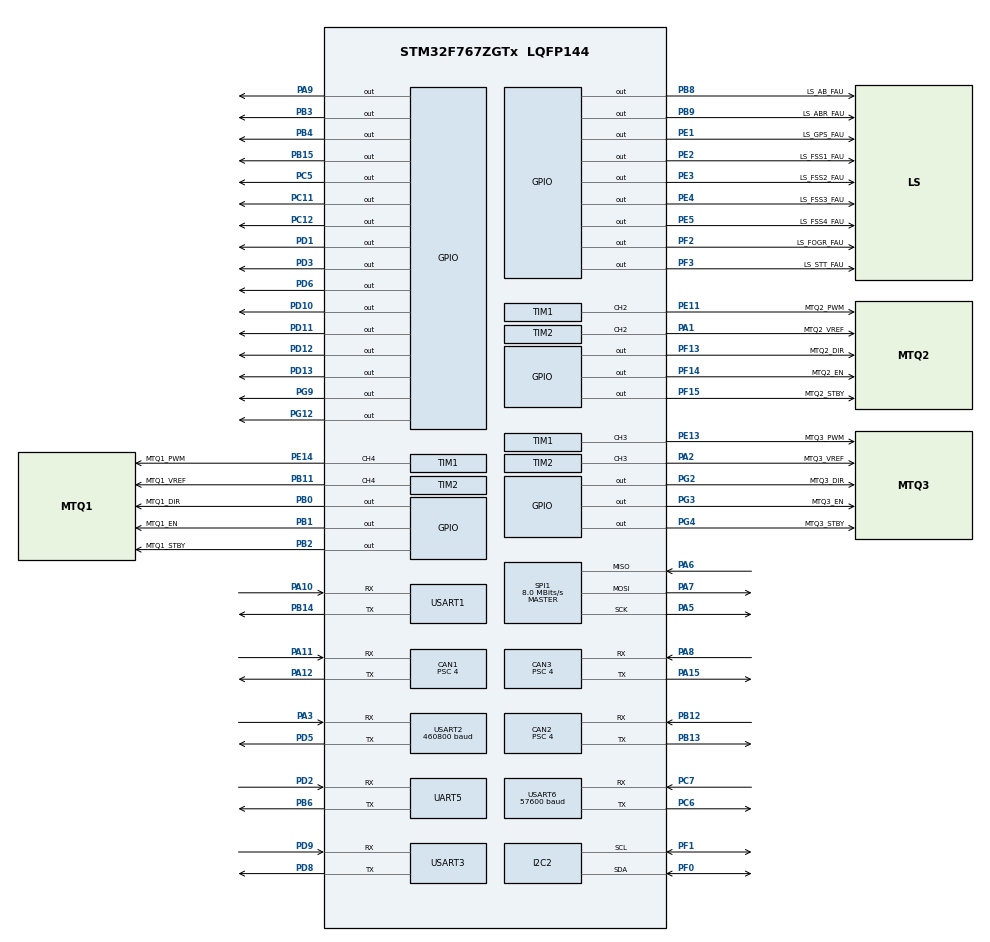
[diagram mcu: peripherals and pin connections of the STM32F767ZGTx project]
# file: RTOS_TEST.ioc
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CAN1.BS1=CAN_BS1_6TQ
CAN1.CalculateBaudRate=1000000
CAN1.CalculateTimeBit=1000
CAN1.CalculateTimeQuantum=125.0
CAN1.Prescaler=4
CAN1.RFLM=DISABLE
CAN1.TXFP=DISABLE
CAN2.BS1=CAN_BS1_6TQ
CAN2.CalculateBaudRate=1000000
CAN2.CalculateTimeBit=1000
CAN2.CalculateTimeQuantum=125.0
CAN2.Prescaler=4
CAN3.BS1=CAN_BS1_6TQ
CAN3.CalculateBaudRate=1000000
CAN3.CalculateTimeBit=1000
CAN3.CalculateTimeQuantum=125.0
CAN3.Prescaler=4
Dma.Request0=USART2_RX
Dma.Request1=USART6_RX
Dma.USART2_RX.0.Direction=DMA_PERIPH_TO_MEMORY
Dma.USART2_RX.0.FIFOMode=DMA_FIFOMODE_DISABLE
Dma.USART2_RX.0.Instance=DMA1_Stream5
Dma.USART2_RX.0.MemDataAlignment=DMA_MDATAALIGN_BYTE
Dma.USART2_RX.0.MemInc=DMA_MINC_ENABLE
Dma.USART2_RX.0.Mode=DMA_NORMAL
Dma.USART2_RX.0.PeriphDataAlignment=DMA_PDATAALIGN_BYTE
Dma.USART2_RX.0.PeriphInc=DMA_PINC_DISABLE
Dma.USART2_RX.0.Priority=DMA_PRIORITY_VERY_HIGH
Dma.USART6_RX.1.Direction=DMA_PERIPH_TO_MEMORY
Dma.USART6_RX.1.FIFOMode=DMA_FIFOMODE_DISABLE
Dma.USART6_RX.1.Instance=DMA2_Stream1
Dma.USART6_RX.1.MemDataAlignment=DMA_MDATAALIGN_BYTE
Dma.USART6_RX.1.MemInc=DMA_MINC_ENABLE
Dma.USART6_RX.1.Mode=DMA_NORMAL
Dma.USART6_RX.1.PeriphDataAlignment=DMA_PDATAALIGN_BYTE
Dma.USART6_RX.1.PeriphInc=DMA_PINC_DISABLE
Dma.USART6_RX.1.Priority=DMA_PRIORITY_MEDIUM
FATFS._MAX_SS=4096
FATFS._USE_LFN=2
FREERTOS.CMSIS_version-CMSIS_V2=undefined
FREERTOS.Tasks01=defaultTask,24,128,StartDefaultTask,Default,NULL,Dynamic,NULL,NULL
FREERTOS.configTOTAL_HEAP_SIZE=125000
FREERTOS.configUSE_NEWLIB_REENTRANT=1
FREERTOS.configUSE_STATS_FORMATTING_FUNCTIONS=1
I2C2.Timing=0x00707CBB
Mcu.Family=STM32F7
Mcu.Name=STM32F767ZGTx
Mcu.Package=LQFP144
NVIC.CAN1_RX0_IRQn=true\:5\:0\:true\:false\:true\:true\:true\:true\:true
NVIC.CAN1_RX1_IRQn=true\:5\:0\:true\:false\:true\:true\:true\:true\:true
NVIC.CAN1_SCE_IRQn=true\:5\:0\:false\:false\:true\:true\:true\:true\:true
NVIC.CAN1_TX_IRQn=true\:5\:0\:false\:false\:true\:true\:true\:true\:true
NVIC.CAN2_RX0_IRQn=true\:5\:0\:false\:false\:true\:true\:true\:true\:true
NVIC.CAN2_RX1_IRQn=true\:5\:0\:false\:false\:true\:true\:true\:true\:true
NVIC.CAN3_RX0_IRQn=true\:5\:0\:false\:false\:true\:true\:true\:true\:true
NVIC.DMA1_Stream5_IRQn=true\:6\:0\:true\:false\:true\:true\:false\:true\:true
NVIC.DMA2_Stream1_IRQn=true\:5\:0\:false\:false\:true\:true\:false\:true\:true
NVIC.PriorityGroup=NVIC_PRIORITYGROUP_4
NVIC.TIM6_DAC_IRQn=true\:15\:0\:false\:false\:true\:false\:false\:true\:true
NVIC.TimeBase=TIM6_DAC_IRQn
NVIC.TimeBaseIP=TIM6
NVIC.UART5_IRQn=true\:5\:0\:false\:false\:true\:true\:true\:true\:true
NVIC.USART2_IRQn=true\:6\:0\:true\:false\:true\:true\:true\:true\:true
NVIC.USART6_IRQn=true\:5\:0\:false\:false\:true\:true\:true\:true\:true
PA1.GPIO_Label=MTQ2_VREF
PA1.Signal=S_TIM2_CH2
PA10.Mode=Asynchronous
PA10.Signal=USART1_RX
PA11.Mode=CAN_Activate
PA11.Signal=CAN1_RX
PA12.Mode=CAN_Activate
PA12.Signal=CAN1_TX
PA13.Mode=Serial_Wire
PA13.Signal=SYS_JTMS-SWDIO
PA14.Mode=Serial_Wire
PA14.Signal=SYS_JTCK-SWCLK
PA15.Mode=CAN_Activate
PA15.Signal=CAN3_TX
PA2.GPIO_Label=MTQ3_VREF
PA2.Signal=S_TIM2_CH3
PA3.Mode=Asynchronous
PA3.Signal=USART2_RX
PA5.Mode=Full_Duplex_Master
PA5.Signal=SPI1_SCK
PA6.Mode=Full_Duplex_Master
PA6.Signal=SPI1_MISO
PA7.Mode=Full_Duplex_Master
PA7.Signal=SPI1_MOSI
PA8.Mode=CAN_Activate
PA8.Signal=CAN3_RX
PA9.Signal=GPIO_Output
PB0.GPIO_Label=MTQ1_DIR
PB0.Signal=GPIO_Output
PB1.GPIO_Label=MTQ1_EN
PB1.Signal=GPIO_Output
PB11.GPIO_Label=MTQ1_VREF
PB11.Signal=S_TIM2_CH4
PB12.Mode=CAN_Activate
PB12.Signal=CAN2_RX
PB13.Mode=CAN_Activate
PB13.Signal=CAN2_TX
PB14.Mode=Asynchronous
PB14.Signal=USART1_TX
PB15.Signal=GPIO_Output
PB2.GPIO_Label=MTQ1_STBY
PB2.Signal=GPIO_Output
PB3.Signal=GPIO_Output
PB4.Signal=GPIO_Output
PB6.Mode=Asynchronous
PB6.Signal=UART5_TX
PB8.GPIO_Label=LS_AB_FAU
PB8.PinState=GPIO_PIN_SET
PB8.Signal=GPIO_Output
PB9.GPIO_Label=LS_ABR_FAU
PB9.PinState=GPIO_PIN_SET
PB9.Signal=GPIO_Output
PC11.Signal=GPIO_Output
PC12.Signal=GPIO_Output
PC5.Signal=GPIO_Output
PC6.Mode=Asynchronous
PC6.Signal=USART6_TX
PC7.Mode=Asynchronous
PC7.Signal=USART6_RX
PD1.Signal=GPIO_Output
PD10.Signal=GPIO_Output
PD11.Signal=GPIO_Output
PD12.Signal=GPIO_Output
PD13.Signal=GPIO_Output
PD2.Mode=Asynchronous
PD2.Signal=UART5_RX
PD3.Signal=GPIO_Output
PD5.Mode=Asynchronous
PD5.Signal=USART2_TX
PD6.Signal=GPIO_Output
PD8.Mode=Asynchronous
PD8.Signal=USART3_TX
PD9.Mode=Asynchronous
PD9.Signal=USART3_RX
PE1.GPIO_Label=LS_GPS_FAU
PE1.PinState=GPIO_PIN_SET
PE1.Signal=GPIO_Output
PE11.GPIO_Label=MTQ2_PWM
PE11.Signal=S_TIM1_CH2
PE13.GPIO_Label=MTQ3_PWM
PE13.Signal=S_TIM1_CH3
PE14.GPIO_Label=MTQ1_PWM
PE14.Signal=S_TIM1_CH4
PE2.GPIO_Label=LS_FSS1_FAU
PE2.PinState=GPIO_PIN_SET
PE2.Signal=GPIO_Output
PE3.GPIO_Label=LS_FSS2_FAU
PE3.PinState=GPIO_PIN_SET
PE3.Signal=GPIO_Output
PE4.GPIO_Label=LS_FSS3_FAU
PE4.PinState=GPIO_PIN_SET
PE4.Signal=GPIO_Output
PE5.GPIO_Label=LS_FSS4_FAU
PE5.PinState=GPIO_PIN_SET
PE5.Signal=GPIO_Output
PF0.Mode=I2C
PF0.Signal=I2C2_SDA
PF1.Mode=I2C
PF1.Signal=I2C2_SCL
PF13.GPIO_Label=MTQ2_DIR
PF13.Signal=GPIO_Output
PF14.GPIO_Label=MTQ2_EN
PF14.Signal=GPIO_Output
PF15.GPIO_Label=MTQ2_STBY
PF15.Signal=GPIO_Output
PF2.GPIO_Label=LS_FOGR_FAU
PF2.PinState=GPIO_PIN_SET
PF2.Signal=GPIO_Output
PF3.GPIO_Label=LS_STT_FAU
PF3.PinState=GPIO_PIN_SET
PF3.Signal=GPIO_Output
PG0.Signal=EVENTOUT
PG12.PinState=GPIO_PIN_SET
PG12.Signal=GPIO_Output
PG2.GPIO_Label=MTQ3_DIR
PG2.Signal=GPIO_Output
PG3.GPIO_Label=MTQ3_EN
PG3.Signal=GPIO_Output
PG4.GPIO_Label=MTQ3_STBY
PG4.Signal=GPIO_Output
PG9.PinState=GPIO_PIN_SET
PG9.Signal=GPIO_Output
PH0/OSC_IN.Mode=HSE-External-Oscillator
PH0/OSC_IN.Signal=RCC_OSC_IN
PH1/OSC_OUT.Mode=HSE-External-Oscillator
PH1/OSC_OUT.Signal=RCC_OSC_OUT
ProjectManager.HeapSize=0x200
ProjectManager.StackSize=0x400
ProjectManager.TargetToolchain=STM32CubeIDE
RCC.AHBFreq_Value=128000000
RCC.APB1CLKDivider=RCC_HCLK_DIV4
RCC.APB1Freq_Value=32000000
RCC.APB1TimFreq_Value=64000000
RCC.APB2CLKDivider=RCC_HCLK_DIV2
RCC.APB2Freq_Value=64000000
RCC.APB2TimFreq_Value=128000000
RCC.CortexFreq_Value=128000000
RCC.HCLKFreq_Value=128000000
RCC.HSE_VALUE=25000000
RCC.HSI_VALUE=16000000
RCC.LSE_VALUE=32768
RCC.PLLM=25
RCC.PLLN=256
RCC.PLLSourceVirtual=RCC_PLLSOURCE_HSE
RCC.SYSCLKFreq_VALUE=128000000
RCC.SYSCLKSource=RCC_SYSCLKSOURCE_PLLCLK
RCC.USBFreq_Value=128000000
RCC.VCOOutputFreq_Value=256000000
SH.S_TIM1_CH2.0=TIM1_CH2,PWM Generation2 CH2
SH.S_TIM1_CH3.0=TIM1_CH3,PWM Generation3 CH3
SH.S_TIM1_CH4.0=TIM1_CH4,PWM Generation4 CH4
SH.S_TIM2_CH2.0=TIM2_CH2,PWM Generation2 CH2
SH.S_TIM2_CH3.0=TIM2_CH3,PWM Generation3 CH3
SH.S_TIM2_CH4.0=TIM2_CH4,PWM Generation4 CH4
SPI1.BaudRatePrescaler=SPI_BAUDRATEPRESCALER_8
SPI1.CRCCalculation=SPI_CRCCALCULATION_DISABLE
SPI1.CalculateBaudRate=8.0 MBits/s
SPI1.DataSize=SPI_DATASIZE_8BIT
SPI1.Direction=SPI_DIRECTION_2LINES
SPI1.Mode=SPI_MODE_MASTER
SPI1.VirtualType=VM_MASTER
TIM1.Channel-PWM\ Generation2\ CH2=TIM_CHANNEL_2
TIM1.Channel-PWM\ Generation3\ CH3=TIM_CHANNEL_3
TIM1.Channel-PWM\ Generation4\ CH4=TIM_CHANNEL_4
TIM1.Period=99
TIM1.Prescaler=31
TIM2.Channel-PWM\ Generation2\ CH2=TIM_CHANNEL_2
TIM2.Channel-PWM\ Generation3\ CH3=TIM_CHANNEL_3
TIM2.Channel-PWM\ Generation4\ CH4=TIM_CHANNEL_4
TIM2.Period=99
TIM2.Prescaler=31
USART1.VirtualMode-Asynchronous=VM_ASYNC
USART2.BaudRate=460800
USART2.VirtualMode-Asynchronous=VM_ASYNC
USART3.VirtualMode-Asynchronous=VM_ASYNC
USART6.BaudRate=57600
USART6.VirtualMode-Asynchronous=VM_ASYNC
VP_FATFS_VS_Generic.Mode=User_defined
VP_FREERTOS_VS_CMSIS_V2.Mode=CMSIS_V2
VP_SYS_VS_tim6.Mode=TIM6
board=custom

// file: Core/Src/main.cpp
/* USER CODE BEGIN Header */
/**
  ******************************************************************************
  * @file           : main.c
  * @brief          : Main program body
  ******************************************************************************
  * @attention
  *
  * Copyright (c) 2024 STMicroelectronics.
  * All rights reserved.
  *
  * This software is licensed under terms that can be found in the LICENSE file
  * in the root directory of this software component.
  * If no LICENSE file comes with this software, it is provided AS-IS.
  *
  ******************************************************************************
  */
/* USER CODE END Header */
#include <stdio.h>
#include <string.h>
#include <unistd.h>
#include <stdlib.h>
#include "main.h"
#include "cmsis_os.h"
#include "can.h"
#include "fatfs.h"
#include "spi.h"
#include "tim.h"
#include "i2c.h"
#include "usart.h"
#include "gpio.h"
#include "dma.h"

#include <include/csp/csp.h>
#include <include/csp/arch/csp_thread.h>
#include "src/drivers/can_stm/f767zgtx_can.h"

/* USER CODE BEGIN PD */
#define MY_SERVER_PORT		10
#define PORT_REGISTER		20
/* USER CODE END PD */

/* USER CODE BEGIN PV */
const char *rtable = NULL;

/* USER CODE END PV */

void SystemClock_Config(void);
void MX_FREERTOS_Init(void);
/* USER CODE BEGIN PFP */

extern void service_adcs_register(csp_conn_t *conn, csp_packet_t *packet);
static CSP_DEFINE_TASK(task_server);
static CSP_DEFINE_TASK(task_client);
int test_csp_server_task(unsigned int task_stack_size,unsigned int task_priority);
int test_csp_client_task(unsigned int task_stack_size,unsigned int task_priority);
int test_csp_server_client_task(unsigned int task_stack_size,unsigned int task_priority);

/* USER CODE END PFP */

/* USER CODE BEGIN 0 */
CSP_DEFINE_TASK(task_server) {

	csp_log_info("Server task started");

	/* Create socket with no specific socket options, e.g. accepts CRC32, HMAC, XTEA, etc. if enabled during compilation */
	csp_socket_t *sock = csp_socket(CSP_SO_NONE);

	/* Bind socket to all ports, e.g. all incoming connections will be handled here */
	csp_bind(sock, CSP_ANY);

	/* Create a backlog of 10 connections, i.e. up to 10 new connections can be queued */
	csp_listen(sock, 10);

	/* Wait for connections and then process packets on the connection */
	while (1) {

		/* Wait for a new connection, 10000 mS timeout */
		csp_conn_t *conn;
		if ((conn = csp_accept(sock, 10000)) == NULL) {
			/* timeout */
			continue;
		}

		/* Read packets on connection, timout is 100 mS */
		csp_packet_t *packet;
		while ((packet = csp_read(conn, 50)) != NULL) {
			switch (csp_conn_dport(conn)) {
			case MY_SERVER_PORT:
				/* Process packet here */
				csp_log_info("Packet received on MY_SERVER_PORT: %s", (char *) packet->data);
				csp_buffer_free(packet);

	//			service_react_v(conn, packet);
				break;

			case PORT_REGISTER:
				service_adcs_register(conn, packet);
				break;

			default:
				/* Call the default CSP service handler, handle pings, buffer use, etc. */
				csp_service_handler(conn, packet);
				break;
			}
		}

		/* Close current connection */
		csp_close(conn);

	}

	return CSP_TASK_RETURN;

}
/* End of server task */

/* Client task sending requests to server task */
CSP_DEFINE_TASK(task_client) {

	csp_log_info("Client task started");

	unsigned int count = 0;

	while (1) {
//csp_ps(12, 1000);csp_ps(16, 1000);csp_ps(21, 1000);
		csp_sleep_ms(1000);

	}

	return CSP_TASK_RETURN;
}
/* End of client task */

int test_csp_server_task(unsigned int task_stack_size,
		unsigned int task_priority) {
	int ret = csp_thread_create(task_server, "SERVER", task_stack_size, NULL,
			task_priority, NULL);
	if (ret != 0) {
		csp_log_error("Failed to start server task, error: %d", ret);
		return ret;
	}
	return CSP_ERR_NONE;
}

int test_csp_client_task(unsigned int task_stack_size,
		unsigned int task_priority) {
	int ret = csp_thread_create(task_client, "CLIENT", task_stack_size, NULL,
			task_priority, NULL);
	if (ret != 0) {
		csp_log_error("Failed to start client task, error: %d", ret);
		return ret;
	}
	return CSP_ERR_NONE;
}

int test_csp_server_client_task(unsigned int task_stack_size,
		unsigned int task_priority) {
	int ret1 = csp_thread_create(task_server, "SERVER", task_stack_size, NULL,
			task_priority, NULL);
	if (ret1 != 0) {
		csp_log_error("Failed to start server task, error: %d", ret1);
		return ret1;
	}
	int ret2 = csp_thread_create(task_client, "CLIENT", task_stack_size, NULL,
			task_priority, NULL);
	if (ret2 != 0) {
		csp_log_error("Failed to start client task, error: %d", ret2);
		return ret2;
	}
	return CSP_ERR_NONE;
}

/* USER CODE END 0 */

int main(void)
{

  /* MCU Configuration--------------------------------------------------------*/

  /* Reset of all peripherals, Initializes the Flash interface and the Systick. */
  HAL_Init();

  /* Configure the system clock */
  SystemClock_Config();

  /* Initialize all configured peripherals */
  MX_DMA_Init();
  MX_GPIO_Init();
  MX_UART5_Init();
  MX_CAN1_Init();
  MX_CAN2_Init();
  MX_CAN3_Init();
  MX_USART3_UART_Init();
  MX_USART6_UART_Init();
  MX_TIM1_Init();
  MX_TIM2_Init();
  MX_SPI1_Init();
  MX_I2C2_Init();
//  MX_FATFS_Init();
  MX_USART2_UART_Init();
  MX_USART1_UART_Init();
  CAN_FilterConfig();
  HAL_CAN_ActivateNotification(&hcan2, CAN_IT_RX_FIFO0_MSG_PENDING);
  HAL_CAN_ActivateNotification(&hcan3, CAN_IT_RX_FIFO0_MSG_PENDING);

//	HAL_CAN_ActivateNotification(&hcan1, CAN_IT_TX_MAILBOX_EMPTY | CAN_IT_RX_FIFO0_MSG_PENDING | CAN_IT_BUSOFF);

  /* Init scheduler */
  osKernelInitialize();

  /* Call init function for freertos objects (in freertos.c) */
  MX_FREERTOS_Init();

    uint8_t address = 12;

//    csp_debug_level_t debud_level = CSP_PROTOCOL ;
//    for (csp_debug_level_t i = static_cast<csp_debug_level_t>(0); i <= CSP_LOCK;i = static_cast<csp_debug_level_t>(static_cast<int>(i)+1)){
//    	csp_debug_set_level(i, (i <= debud_level)? true:false);
//    }

    	csp_log_info("Initialising CSP\r\n");
    	/* Init CSP with address and default settings */
    	csp_conf_t csp_conf;
    	csp_conf_get_defaults(&csp_conf);
    	csp_conf.address = address;
    	int error = csp_init(&csp_conf);
    	if (error != CSP_ERR_NONE) {
    		csp_log_error("csp_init() failed, error: %d", error);
    		exit(1);
    	}

    	csp_route_start_task(500, osPriorityRealtime);
    	csp_iface_t *default_iface = NULL;

    	/* Add interface(s) */
    	//

    	csp_driver_can_init(0, CSP_CAN_PROMISC, &default_iface);
    	csp_driver_can_init1(1, CSP_CAN_PROMISC, &default_iface);
    	//rtable = "19 LOOP, 0/0 CAN";
    	rtable = "0/0 CAN, 16/5 CAN_A, 17/5 CAN_A";
    	//rtable = "0/0 CAN";
    	//rtable = "0/0 CAN_A";
    	if (rtable) {
    		error = csp_rtable_load(rtable);
    		if (error < 1) {
    			csp_log_error("csp_rtable_load(%s) failed, error: %d", rtable,
    					error);
    			exit(1);
    		}
    	} else if (default_iface) {
    		csp_rtable_set(CSP_DEFAULT_ROUTE, 0, default_iface, CSP_NO_VIA_ADDRESS);
    	} else {
    		/* no interfaces configured - run server and client in process, using loopback interface */
    	}

    	printf("Connection table\r\n");
//    	csp_conn_print_table();

    	printf("Interfaces\r\n");
    	csp_route_print_interfaces();

    	printf("Route table\r\n");
    	csp_route_print_table();
    	//test_csp_server_client_task(500, osPriorityAboveNormal);
    	test_csp_server_task(500, osPriorityAboveNormal);
    	//test_csp_client_task(500, osPriorityAboveNormal);

  /* Start scheduler */
  osKernelStart();

  /* We should never get here as control is now taken by the scheduler */
  /* Infinite loop */
  while (1)
  {
	  int res = HAL_CAN_GetRxFifoFillLevel(&hcan2, CAN_RX_FIFO0);
	  int re3 = HAL_CAN_GetRxFifoFillLevel(&hcan2, CAN_RX_FIFO1);

	  if(res >0 || re3 >0){
		  Error_Handler();
	  }
	  HAL_Delay(1);
  }
}

void SystemClock_Config(void)
{
  RCC_OscInitTypeDef RCC_OscInitStruct = {0};
  RCC_ClkInitTypeDef RCC_ClkInitStruct = {0};

  /** Configure the main internal regulator output voltage
  */
  __HAL_RCC_PWR_CLK_ENABLE();
  __HAL_PWR_VOLTAGESCALING_CONFIG(PWR_REGULATOR_VOLTAGE_SCALE3);

  /** Initializes the RCC Oscillators according to the specified parameters
  * in the RCC_OscInitTypeDef structure.
  */
  RCC_OscInitStruct.OscillatorType = RCC_OSCILLATORTYPE_HSI;
  RCC_OscInitStruct.HSIState = RCC_HSI_ON;
  RCC_OscInitStruct.HSICalibrationValue = RCC_HSICALIBRATION_DEFAULT;
  RCC_OscInitStruct.PLL.PLLState = RCC_PLL_ON;
  RCC_OscInitStruct.PLL.PLLSource = RCC_PLLSOURCE_HSI;
  RCC_OscInitStruct.PLL.PLLM = 8;
  RCC_OscInitStruct.PLL.PLLN = 128;
  RCC_OscInitStruct.PLL.PLLP = RCC_PLLP_DIV2;
  RCC_OscInitStruct.PLL.PLLQ = 2;
  RCC_OscInitStruct.PLL.PLLR = 2;
  if (HAL_RCC_OscConfig(&RCC_OscInitStruct) != HAL_OK)
  {
    Error_Handler();
  }

  /** Initializes the CPU, AHB and APB buses clocks
  */
  RCC_ClkInitStruct.ClockType = RCC_CLOCKTYPE_HCLK|RCC_CLOCKTYPE_SYSCLK
                              |RCC_CLOCKTYPE_PCLK1|RCC_CLOCKTYPE_PCLK2;
  RCC_ClkInitStruct.SYSCLKSource = RCC_SYSCLKSOURCE_PLLCLK;
  RCC_ClkInitStruct.AHBCLKDivider = RCC_SYSCLK_DIV2;
  RCC_ClkInitStruct.APB1CLKDivider = RCC_HCLK_DIV2;
  RCC_ClkInitStruct.APB2CLKDivider = RCC_HCLK_DIV1;

  if (HAL_RCC_ClockConfig(&RCC_ClkInitStruct, FLASH_LATENCY_2) != HAL_OK)
  {
    Error_Handler();
  }
}

void HAL_TIM_PeriodElapsedCallback(TIM_HandleTypeDef *htim)
{
  if (htim->Instance == TIM6) {
    HAL_IncTick();
  }
}

void Error_Handler(void)
{
  __disable_irq();
  while (1)
  {
  }
}
